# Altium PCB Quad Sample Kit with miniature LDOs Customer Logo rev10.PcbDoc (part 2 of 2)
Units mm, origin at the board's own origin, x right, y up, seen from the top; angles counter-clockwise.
Board outline 152.4 x 101.6 mm, 2 copper layers (Top Layer, Bottom Layer); 23 components, 21 nets, 109 pads, 47 vias.
Unrouted connection lines stored in the file: 13.

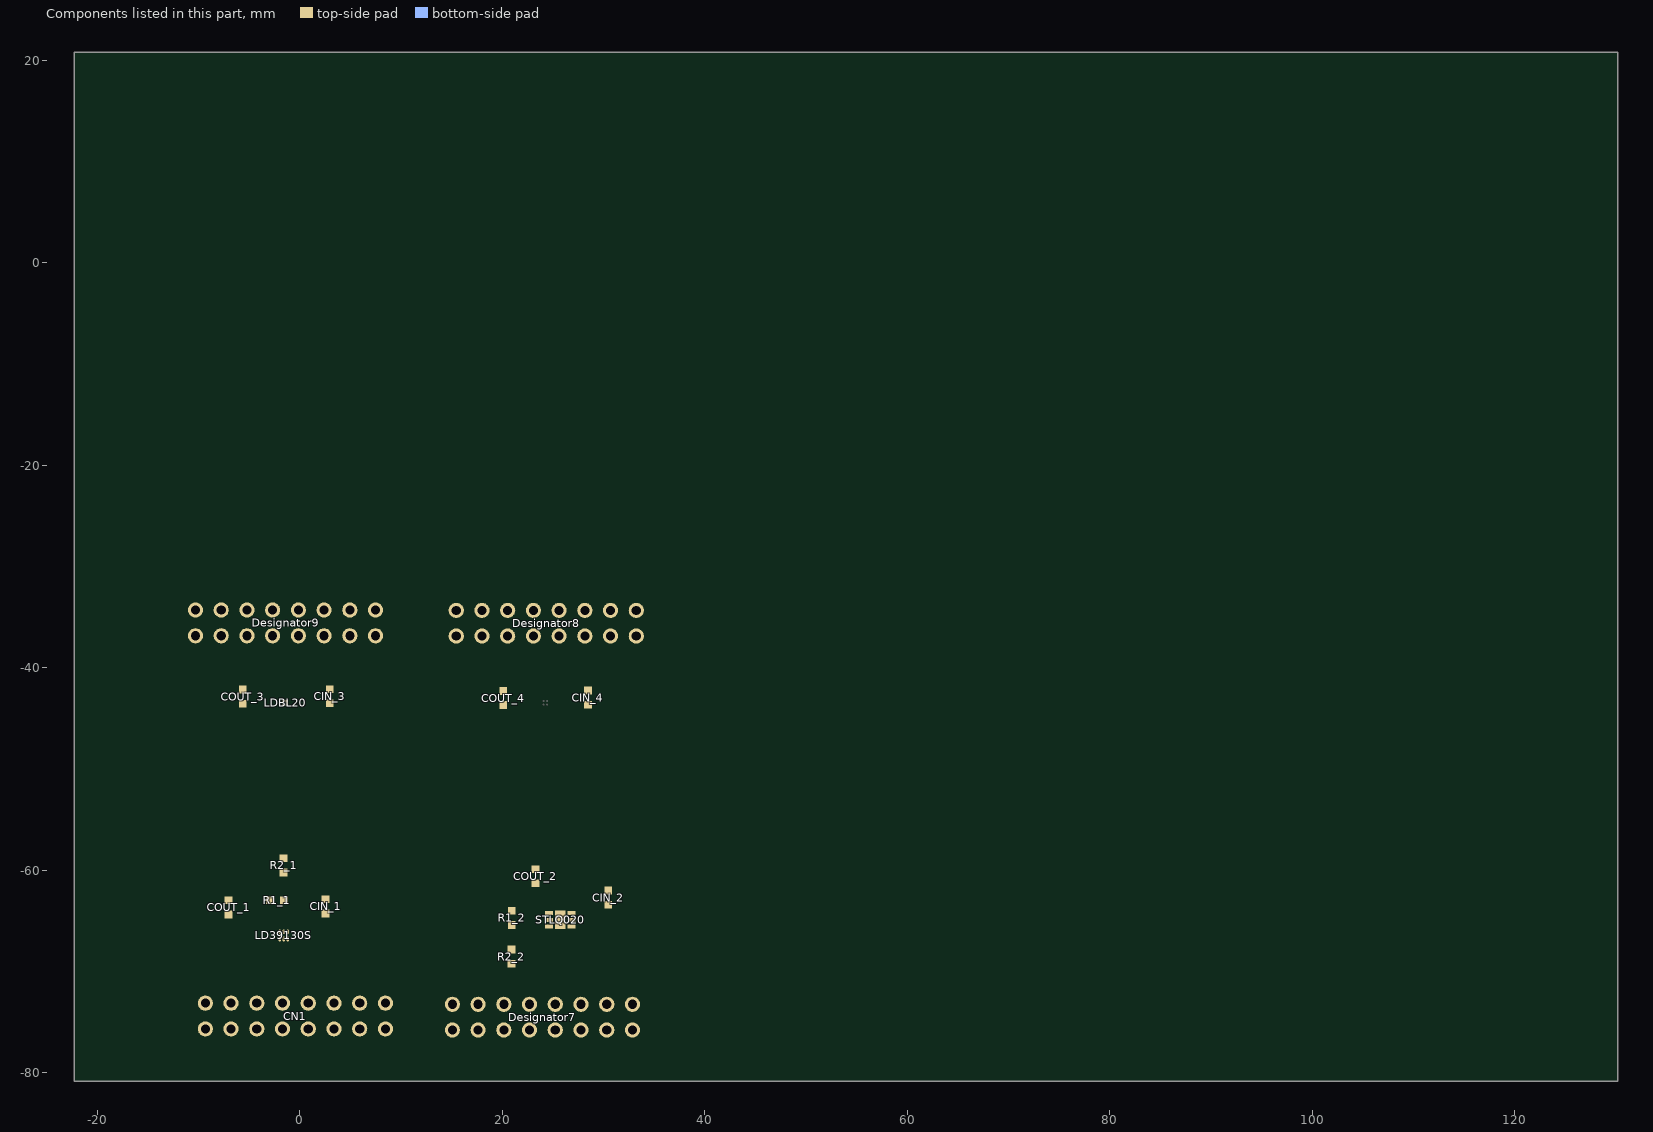
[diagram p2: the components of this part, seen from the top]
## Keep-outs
Bottom Overlay:
  lines w0.038: 1.384,-57.277 7.988,-57.277 ; 1.384,-57.252 7.988,-57.252 ; 1.384,-57.226 7.988,-57.226 ; 1.384,-57.201 7.988,-57.201 ; 1.384,-57.176 7.988,-57.176 ; 1.384,-57.15 7.988,-57.15 ; 1.384,-57.125 7.988,-57.125 ; 1.384,-57.099 7.988,-57.099 ; 1.384,-57.074 7.988,-57.074 ; 1.384,-57.049 7.988,-57.049 ; 1.384,-57.023 7.988,-57.023 ; 1.384,-56.998 1.587,-56.998 ; 1.384,-56.972 1.587,-56.972 ; 1.384,-56.947 1.587,-56.947 ; 1.384,-56.922 1.587,-56.922 ; 1.384,-56.896 1.587,-56.896 ; 1.384,-56.871 1.587,-56.871 ; 1.384,-56.845 1.587,-56.845 ; 1.384,-56.82 1.587,-56.82 ; 1.384,-56.795 1.587,-56.795 ; 1.384,-56.769 1.587,-56.769 ; 1.384,-56.744 1.587,-56.744 ; 1.384,-56.718 1.587,-56.718 ; 1.384,-56.693 1.587,-56.693 ; 1.384,-56.668 1.587,-56.668 ; 1.384,-56.642 1.587,-56.642 ; 1.384,-56.617 1.587,-56.617 ; 1.384,-56.591 1.587,-56.591 ; 1.384,-56.566 1.587,-56.566 ; 1.384,-56.541 1.587,-56.541 ; 1.384,-56.515 1.587,-56.515 ; 1.384,-56.49 1.587,-56.49 ; 1.384,-56.464 1.587,-56.464 ; 1.384,-56.439 1.587,-56.439 ; 1.384,-56.414 1.587,-56.414 ; 1.384,-56.388 1.587,-56.388 ; 1.384,-56.363 1.587,-56.363 ; 1.384,-56.337 1.587,-56.337 ; 1.384,-56.312 1.587,-56.312 ; 1.384,-56.287 1.587,-56.287 ; 1.384,-56.261 1.587,-56.261 ; 1.384,-56.236 1.587,-56.236 ; 1.384,-56.21 1.587,-56.21 ; 1.384,-56.185 1.587,-56.185 ; 1.384,-56.16 1.587,-56.16 ; 1.384,-56.134 1.587,-56.134 ; 1.384,-56.109 1.587,-56.109 ; 1.384,-56.083 1.587,-56.083 ; 1.384,-56.058 1.587,-56.058 ; 1.384,-56.033 1.587,-56.033 ; 1.384,-56.007 1.587,-56.007 ; 1.384,-55.982 1.587,-55.982 ; 1.384,-55.956 1.587,-55.956 ; 1.384,-55.931 1.587,-55.931 ; 1.384,-55.906 1.587,-55.906 ; 1.384,-55.88 1.587,-55.88 ; 1.384,-55.855 1.587,-55.855 ; 1.384,-55.829 1.587,-55.829 ; 1.384,-55.804 1.587,-55.804 ; 1.384,-55.779 1.587,-55.779 ; 1.384,-55.753 1.587,-55.753 ; 1.384,-55.728 1.587,-55.728 ; 1.384,-55.702 1.587,-55.702 ; 1.384,-55.677 1.587,-55.677 ; 1.384,-55.652 1.587,-55.652 ; 1.384,-55.626 1.587,-55.626 ; 1.384,-55.601 1.587,-55.601 ; 1.384,-55.575 1.587,-55.575 ; 1.384,-55.55 1.587,-55.55 ; 1.384,-55.525 1.587,-55.525 ; 1.384,-55.499 1.587,-55.499 ; 1.384,-55.474 1.587,-55.474 ; 1.384,-55.448 1.587,-55.448 ; 1.384,-55.423 1.587,-55.423 ; 1.384,-55.398 1.587,-55.398 ; 1.384,-55.372 1.587,-55.372 ; 1.384,-55.347 1.587,-55.347 ; 1.384,-55.321 1.587,-55.321 ; 1.384,-55.296 1.587,-55.296 ; 1.384,-55.271 1.587,-55.271 ; 1.384,-55.245 1.587,-55.245 ; 1.384,-55.22 1.587,-55.22 ; 1.384,-55.194 1.587,-55.194 ; 1.384,-55.169 1.587,-55.169 ; 1.384,-55.144 1.587,-55.144 ; 1.384,-55.118 1.587,-55.118 ; 1.384,-55.093 1.587,-55.093 ; 1.384,-55.067 1.587,-55.067 ; 1.384,-55.042 1.587,-55.042 ; 1.384,-55.017 1.587,-55.017 ; 1.384,-54.991 1.587,-54.991 ; 1.384,-54.966 1.587,-54.966 ; 1.384,-54.94 1.587,-54.94 ; 1.384,-54.915 1.587,-54.915 ; 1.384,-54.89 1.587,-54.89 ; 1.384,-54.864 1.587,-54.864 ; 1.384,-54.839 1.587,-54.839 ; 1.384,-54.813 1.587,-54.813 ; 1.384,-54.788 1.587,-54.788 ; 1.384,-54.763 1.587,-54.763 ; 1.384,-54.737 1.587,-54.737 ; 1.384,-54.712 1.587,-54.712 ; 1.384,-54.686 1.587,-54.686 ; 1.384,-54.661 1.587,-54.661 ; 1.384,-54.636 1.587,-54.636 ; 1.384,-54.61 1.587,-54.61 ; 1.384,-54.585 1.587,-54.585 ; 1.384,-54.559 1.587,-54.559 ; 1.384,-54.534 1.587,-54.534 ; 1.384,-54.509 1.587,-54.509 ; 1.384,-54.483 1.587,-54.483 ; 1.384,-54.458 1.587,-54.458 ; 1.384,-54.432 1.587,-54.432 ; 1.384,-54.407 1.587,-54.407 ; 1.384,-54.382 1.587,-54.382 ; 1.384,-54.356 1.587,-54.356 ; 1.384,-54.331 1.587,-54.331 ; 1.384,-54.305 1.587,-54.305 ; 1.384,-54.28 1.587,-54.28 ; 1.384,-54.255 1.587,-54.255 ; 1.384,-54.229 1.587,-54.229 ; 1.384,-54.204 1.587,-54.204 ; 1.384,-54.178 1.587,-54.178 ; 1.384,-54.153 1.587,-54.153 ; 1.384,-54.128 1.587,-54.128 ; 1.384,-54.102 1.587,-54.102 ; 1.384,-54.077 1.587,-54.077 ; 1.384,-54.051 1.587,-54.051 ; 1.384,-54.026 1.587,-54.026 ; 1.384,-54.001 1.587,-54.001 ; 1.384,-53.975 1.587,-53.975 ; 1.384,-53.95 1.587,-53.95 ; 1.384,-53.924 1.587,-53.924 ; 1.384,-53.899 1.587,-53.899 ; 1.384,-53.874 1.587,-53.874 ; 1.384,-53.848 1.587,-53.848 ; 1.384,-53.823 1.587,-53.823 ; 1.384,-53.797 1.587,-53.797 ; 1.384,-53.772 1.587,-53.772 ; 1.384,-53.747 1.587,-53.747 ; 1.384,-53.721 1.587,-53.721 ; 1.384,-53.696 1.587,-53.696 ; 1.384,-53.67 1.587,-53.67 ; 1.384,-53.645 1.587,-53.645 ; 1.384,-53.62 1.587,-53.62 ; 1.384,-53.594 1.587,-53.594 ; 1.384,-53.569 1.587,-53.569 ; 1.384,-53.543 1.587,-53.543 ; 1.384,-53.518 1.587,-53.518 ; 1.384,-53.493 1.587,-53.493 ; 1.384,-53.467 1.587,-53.467 ; 1.384,-53.442 1.587,-53.442 ; 1.384,-53.416 1.587,-53.416 ; 1.384,-53.391 1.587,-53.391 ; 1.384,-53.366 1.587,-53.366 ; 1.384,-53.34 1.587,-53.34 ; 1.384,-53.315 1.587,-53.315 ; 1.384,-53.289 1.587,-53.289 ; 1.384,-53.264 1.587,-53.264 ; 1.384,-53.239 1.587,-53.239 ; 1.384,-53.213 1.587,-53.213 ; 1.384,-53.188 1.587,-53.188 ; 1.384,-53.162 1.587,-53.162 ; 1.384,-53.137 1.587,-53.137 ; 1.384,-53.112 1.587,-53.112 ; 1.384,-53.086 1.587,-53.086 ; 1.384,-53.061 1.587,-53.061 ; 1.384,-53.035 1.587,-53.035 ; 1.384,-53.01 1.587,-53.01 ; 1.384,-52.985 1.587,-52.985 ; 1.384,-52.959 1.587,-52.959 ; 1.384,-52.934 1.587,-52.934 ; 1.384,-52.908 1.587,-52.908 ; 1.384,-52.883 1.587,-52.883 ; 1.384,-52.858 1.587,-52.858 ; 1.384,-52.832 1.587,-52.832 ; 1.384,-52.807 1.587,-52.807 ; 1.384,-52.781 1.587,-52.781 ; 1.384,-52.756 1.587,-52.756 ; 1.384,-52.731 1.587,-52.731 ; 1.384,-52.705 1.587,-52.705 ; 1.384,-52.68 1.587,-52.68 ; 1.384,-52.654 7.988,-52.654 ; 1.384,-52.629 7.988,-52.629 ; 1.384,-52.604 7.988,-52.604 ; 1.384,-52.578 7.988,-52.578 ; 1.384,-52.553 7.988,-52.553 ; 1.384,-52.527 7.988,-52.527 ; 1.384,-52.502 7.988,-52.502 ; 1.384,-52.477 7.988,-52.477 ; 1.849,-55.164 2.408,-55.164 ; 1.849,-55.139 2.408,-55.139 ; 1.849,-55.113 2.408,-55.113 ; 1.849,-55.088 2.408,-55.088 ; 1.849,-55.062 2.408,-55.062 ; 2.027,-55.621 2.23,-55.621 ; 2.027,-55.595 2.23,-55.595 ; 2.027,-55.57 2.23,-55.57 ; 2.027,-55.544 2.23,-55.544 ; 2.027,-55.519 2.23,-55.519 ; 2.027,-55.494 2.23,-55.494 ; 2.027,-55.468 2.23,-55.468 ; 2.027,-55.443 2.23,-55.443 ; 2.027,-55.417 2.23,-55.417 ; 2.027,-55.393 2.23,-55.393 ; 2.027,-55.367 2.23,-55.367 ; 2.027,-55.342 2.23,-55.342 ; 2.027,-55.316 2.23,-55.316 ; 2.027,-55.291 2.23,-55.291 ; 2.027,-55.266 2.23,-55.266 ; 2.027,-55.24 2.23,-55.24 ; 2.027,-55.215 2.23,-55.215 ; 2.027,-55.189 2.23,-55.189 ; 2.248,-54.128 2.679,-54.128 ; 2.248,-54.102 2.679,-54.102 ; 2.248,-54.077 2.654,-54.077 ; 2.248,-54.051 2.654,-54.051 ; 2.248,-54.026 2.654,-54.026 ; 2.248,-54.001 2.679,-54.001 ; 2.248,-53.975 2.73,-53.975 ; 2.248,-53.95 2.781,-53.95 ; 2.273,-54.178 3.34,-54.178 ; 2.273,-54.153 2.73,-54.153 ; 2.273,-53.924 2.908,-53.924 ; 2.273,-53.899 2.984,-53.899 ; 2.273,-53.874 3.06,-53.874 ; 2.273,-53.569 2.679,-53.569 ; 2.273,-53.543 2.705,-53.543 ; 2.273,-53.518 2.705,-53.518 ; 2.298,-54.229 3.314,-54.229 ; 2.298,-54.204 3.314,-54.204 ; 2.298,-53.848 3.111,-53.848 ; 2.298,-53.493 2.73,-53.493 ; 2.298,-53.467 2.756,-53.467 ; 2.298,-53.442 3.289,-53.442 ; 2.324,-54.255 3.289,-54.255 ; 2.324,-53.823 3.162,-53.823 ; 2.324,-53.797 3.213,-53.797 ; 2.324,-53.416 3.264,-53.416 ; 2.324,-53.391 3.264,-53.391 ; 2.349,-54.305 3.238,-54.305 ; 2.349,-54.28 3.264,-54.28 ; 2.349,-53.772 3.238,-53.772 ; 2.349,-53.594 2.679,-53.594 ; 2.349,-53.366 3.238,-53.366 ; 2.375,-53.34 3.213,-53.34 ; 2.4,-54.331 3.238,-54.331 ; 2.4,-53.747 3.264,-53.747 ; 2.4,-53.315 3.187,-53.315 ; 2.425,-54.356 3.187,-54.356 ; 2.425,-53.721 3.264,-53.721 ; 2.451,-56.388 2.629,-56.388 ; 2.451,-53.289 3.137,-53.289 ; 2.476,-56.439 2.908,-56.439 ; 2.476,-56.414 2.654,-56.414 ; 2.476,-56.16 2.629,-56.16 ; 2.476,-56.134 2.654,-56.134 ; 2.476,-56.109 2.908,-56.109 ; 2.476,-54.382 3.162,-54.382 ; 2.476,-53.696 3.289,-53.696 ; 2.484,-55.621 2.662,-55.621 ; 2.484,-55.595 2.687,-55.595 ; 2.484,-55.57 2.713,-55.57 ; 2.484,-55.544 2.713,-55.544 ; 2.484,-55.519 2.738,-55.519 ; 2.484,-55.494 2.764,-55.494 ; 2.484,-55.468 2.764,-55.468 ; 2.484,-55.443 2.789,-55.443 ; 2.484,-55.417 2.814,-55.417 ; 2.484,-55.393 2.84,-55.393 ; 2.484,-55.367 2.84,-55.367 ; 2.484,-55.342 2.662,-55.342 ; 2.484,-55.316 2.662,-55.316 ; 2.484,-55.291 2.662,-55.291 ; 2.484,-55.266 2.662,-55.266 ; 2.484,-55.24 2.662,-55.24 ; 2.484,-55.215 2.662,-55.215 ; 2.484,-55.189 2.662,-55.189 ; 2.484,-55.164 2.662,-55.164 ; 2.484,-55.139 2.662,-55.139 ; 2.484,-55.113 2.662,-55.113 ; 2.484,-55.088 2.662,-55.088 ; 2.484,-55.062 2.662,-55.062 ; 2.502,-56.464 2.883,-56.464 ; 2.502,-56.363 2.629,-56.363 ; 2.502,-56.083 2.908,-56.083 ; 2.502,-53.264 3.086,-53.264 ; 2.527,-56.49 2.883,-56.49 ; 2.527,-56.058 2.883,-56.058 ; 2.527,-54.407 3.086,-54.407 ; 2.552,-56.515 2.832,-56.515 ; 2.552,-56.033 2.832,-56.033 ; 2.552,-53.67 3.289,-53.67 ; 2.603,-56.337 2.629,-56.337 ; 2.603,-56.185 2.629,-56.185 ; 2.603,-54.432 3.01,-54.432 ; 2.603,-53.239 2.984,-53.239 ; 2.629,-56.541 2.756,-56.541 ; 2.629,-56.007 2.756,-56.007 ; 2.629,-53.645 3.314,-53.645 ; 2.687,-55.342 2.865,-55.342 ; 2.713,-55.316 3.068,-55.316 ; 2.713,-55.291 3.068,-55.291 ; 2.73,-53.62 3.314,-53.62 ; 2.738,-55.266 3.068,-55.266 ; 2.756,-56.414 2.933,-56.414 ; 2.756,-56.16 2.933,-56.16 ; 2.756,-56.134 2.933,-56.134 ; 2.764,-55.24 3.068,-55.24 ; 2.781,-56.388 2.933,-56.388 ; 2.781,-56.363 2.933,-56.363 ; 2.781,-56.337 2.933,-56.337 ; 2.781,-56.312 2.959,-56.312 ; 2.781,-56.287 2.959,-56.287 ; 2.781,-56.261 2.959,-56.261 ; 2.781,-56.236 2.959,-56.236 ; 2.781,-56.21 2.959,-56.21 ; 2.781,-56.185 2.933,-56.185 ; 2.789,-55.215 3.068,-55.215 ; 2.789,-55.189 3.068,-55.189 ; 2.814,-55.164 3.068,-55.164 ; 2.832,-54.153 3.34,-54.153 ; 2.832,-53.594 3.314,-53.594 ; 2.84,-55.139 3.068,-55.139 ; 2.84,-55.113 3.068,-55.113 ; 2.857,-53.467 3.289,-53.467 ; 2.865,-55.088 3.068,-55.088 ; 2.883,-54.128 3.34,-54.128 ; 2.883,-53.569 3.314,-53.569 ; 2.883,-53.493 3.314,-53.493 ; 2.891,-55.621 3.068,-55.621 ; 2.891,-55.595 3.068,-55.595 ; 2.891,-55.57 3.068,-55.57 ; 2.891,-55.544 3.068,-55.544 ; 2.891,-55.519 3.068,-55.519 ; 2.891,-55.494 3.068,-55.494 ; 2.891,-55.468 3.068,-55.468 ; 2.891,-55.443 3.068,-55.443 ; 2.891,-55.417 3.068,-55.417 ; 2.891,-55.393 3.068,-55.393 ; 2.891,-55.367 3.068,-55.367 ; 2.891,-55.342 3.068,-55.342 ; 2.891,-55.062 3.068,-55.062 ; 2.908,-54.102 3.365,-54.102 ; 2.908,-53.543 3.314,-53.543 ; 2.908,-53.518 3.314,-53.518 ; 2.933,-54.077 3.365,-54.077 ; 2.933,-54.051 3.365,-54.051 ; 2.959,-54.026 3.365,-54.026 ; 2.959,-54.001 3.314,-54.001 ; 3.035,-56.541 3.492,-56.541 ; 3.035,-56.515 3.492,-56.515 ; 3.035,-56.49 3.492,-56.49 ; 3.035,-56.464 3.492,-56.464 ; 3.035,-56.439 3.492,-56.439 ; 3.035,-56.109 3.492,-56.109 ; 3.035,-56.083 3.492,-56.083 ; 3.035,-56.058 3.492,-56.058 ; 3.035,-56.033 3.492,-56.033 ; 3.035,-56.007 3.492,-56.007 ; 3.06,-56.312 3.492,-56.312 ; 3.06,-56.287 3.492,-56.287 ; 3.06,-56.261 3.492,-56.261 ; 3.06,-56.236 3.492,-56.236 ; 3.06,-56.21 3.492,-56.21 ; 3.144,-55.611 3.347,-55.611 ; 3.169,-55.585 3.372,-55.585 ; 3.169,-55.56 3.372,-55.56 ; 3.169,-55.534 3.372,-55.534 ; 3.195,-55.509 3.753,-55.509 ; 3.195,-55.484 3.753,-55.484 ; 3.195,-55.458 3.753,-55.458 ; 3.22,-55.433 3.728,-55.433 ; 3.22,-55.407 3.728,-55.407 ; 3.22,-55.382 3.728,-55.382 ; 3.245,-55.357 3.423,-55.357 ; 3.245,-55.332 3.423,-55.332 ; 3.245,-55.306 3.449,-55.306 ; 3.271,-55.281 3.449,-55.281 ; 3.271,-55.255 3.449,-55.255 ; 3.271,-55.23 3.677,-55.23 ; 3.296,-55.205 3.652,-55.205 ; 3.296,-55.179 3.652,-55.179 ; 3.296,-55.154 3.652,-55.154 ; 3.314,-56.414 3.492,-56.414 ; 3.314,-56.388 3.492,-56.388 ; 3.314,-56.363 3.492,-56.363 ; 3.314,-56.337 3.492,-56.337 ; 3.314,-56.185 3.492,-56.185 ; 3.314,-56.16 3.492,-56.16 ; 3.314,-56.134 3.492,-56.134 ; 3.322,-55.128 3.626,-55.128 ; 3.322,-55.103 3.626,-55.103 ; 3.322,-55.078 3.626,-55.078 ; 3.347,-55.052 3.601,-55.052 ; 3.499,-55.306 3.703,-55.306 ; 3.499,-55.281 3.677,-55.281 ; 3.499,-55.255 3.677,-55.255 ; 3.518,-54.407 3.924,-54.407 ; 3.518,-54.382 3.924,-54.382 ; 3.518,-54.356 3.924,-54.356 ; 3.518,-54.331 3.924,-54.331 ; 3.518,-54.305 3.924,-54.305 ; 3.518,-54.28 3.924,-54.28 ; 3.518,-54.255 3.924,-54.255 ; 3.518,-54.229 3.924,-54.229 ; 3.518,-54.204 3.924,-54.204 ; 3.518,-54.178 3.924,-54.178 ; 3.518,-54.153 3.924,-54.153 ; 3.518,-54.128 3.924,-54.128 ; 3.518,-54.102 3.924,-54.102 ; 3.518,-54.077 3.924,-54.077 ; 3.518,-54.051 3.924,-54.051 ; 3.518,-54.026 3.924,-54.026 ; 3.518,-54.001 3.924,-54.001 ; 3.518,-53.975 3.924,-53.975 ; 3.518,-53.95 4.635,-53.95 ; 3.518,-53.924 4.635,-53.924 ; 3.518,-53.899 4.635,-53.899 ; 3.518,-53.874 4.635,-53.874 ; 3.518,-53.848 4.635,-53.848 ; 3.518,-53.823 4.635,-53.823 ; 3.518,-53.797 4.635,-53.797 ; 3.518,-53.772 4.635,-53.772 ; 3.518,-53.747 4.635,-53.747 ; 3.518,-53.721 4.635,-53.721 ; 3.518,-53.696 4.635,-53.696 ; 3.518,-53.67 4.635,-53.67 ; 3.518,-53.645 3.924,-53.645 ; 3.518,-53.62 3.924,-53.62 ; 3.518,-53.594 3.924,-53.594 ; 3.518,-53.569 3.924,-53.569 ; 3.518,-53.543 3.924,-53.543 ; 3.518,-53.518 3.924,-53.518 ; 3.518,-53.493 3.924,-53.493 ; 3.518,-53.467 3.924,-53.467 ; 3.518,-53.442 3.924,-53.442 ; 3.518,-53.416 3.924,-53.416 ; 3.518,-53.391 3.924,-53.391 ; 3.518,-53.366 3.924,-53.366 ; 3.518,-53.34 3.924,-53.34 ; 3.518,-53.315 3.924,-53.315 ; 3.518,-53.289 3.924,-53.289 ; 3.518,-53.264 3.924,-53.264 ; 3.525,-55.357 3.703,-55.357 ; 3.525,-55.332 3.703,-55.332 ; 3.543,-56.007 3.619,-56.007 ; 3.568,-56.109 3.645,-56.109 ; 3.568,-56.083 3.645,-56.083 ; 3.568,-56.058 3.619,-56.058 ; 3.568,-56.033 3.619,-56.033 ; 3.576,-55.585 3.779,-55.585 ; 3.576,-55.56 3.779,-55.56 ; 3.576,-55.534 3.779,-55.534 ; 3.594,-56.236 3.67,-56.236 ; 3.594,-56.21 3.67,-56.21 ; 3.594,-56.185 3.645,-56.185 ; 3.594,-56.16 3.645,-56.16 ; 3.594,-56.134 3.645,-56.134 ; 3.601,-55.611 3.804,-55.611 ; 3.619,-56.337 3.695,-56.337 ; 3.619,-56.312 3.695,-56.312 ; 3.619,-56.287 3.67,-56.287 ; 3.619,-56.261 3.67,-56.261 ; 3.645,-56.464 3.721,-56.464 ; 3.645,-56.439 3.721,-56.439 ; 3.645,-56.414 3.695,-56.414 ; 3.645,-56.388 3.695,-56.388 ; 3.645,-56.363 3.695,-56.363 ; 3.67,-56.541 3.746,-56.541 ; 3.67,-56.515 3.721,-56.515 ; 3.67,-56.49 3.721,-56.49 ; 3.797,-56.388 3.949,-56.388 ; 3.797,-56.363 3.949,-56.363 ; 3.797,-56.337 3.949,-56.337 ; 3.797,-56.312 3.949,-56.312 ; 3.822,-56.439 3.975,-56.439 ; 3.822,-56.414 3.949,-56.414 ; 3.822,-56.287 3.975,-56.287 ; 3.822,-56.261 4.178,-56.261 ; 3.822,-56.109 4.153,-56.109 ; 3.822,-56.083 4.153,-56.083 ; 3.822,-56.058 4.153,-56.058 ; 3.822,-56.033 4.153,-56.033 ; 3.822,-56.007 4.153,-56.007 ; 3.848,-56.49 4.178,-56.49 ; 3.848,-56.464 4.203,-56.464 ; 3.848,-56.236 4.178,-56.236 ; 3.873,-56.515 4.153,-56.515 ; 3.873,-56.21 4.178,-56.21 ; 3.915,-55.611 4.118,-55.611 ; 3.915,-55.585 4.118,-55.585 ; 3.915,-55.56 4.118,-55.56 ; 3.915,-55.534 4.118,-55.534 ; 3.915,-55.509 4.118,-55.509 ; 3.915,-55.484 4.118,-55.484 ; 3.915,-55.458 4.118,-55.458 ; 3.915,-55.433 4.118,-55.433 ; 3.915,-55.407 4.118,-55.407 ; 3.915,-55.382 4.118,-55.382 ; 3.915,-55.357 4.118,-55.357 ; 3.915,-55.332 4.118,-55.332 ; 3.915,-55.306 4.118,-55.306 ; 3.915,-55.281 4.118,-55.281 ; 3.915,-55.255 4.118,-55.255 ; 3.915,-55.23 4.118,-55.23 ; 3.915,-55.205 4.118,-55.205 ; 3.915,-55.179 4.118,-55.179 ; 3.915,-55.154 4.118,-55.154 ; 3.915,-55.128 4.118,-55.128 ; 3.915,-55.103 4.118,-55.103 ; 3.915,-55.078 4.118,-55.078 ; 3.915,-55.052 4.118,-55.052 ; 3.924,-56.185 4,-56.185 ; 3.949,-56.541 4.076,-56.541 ; 4.051,-56.439 4.203,-56.439 ; 4.051,-56.287 4.178,-56.287 ; 4.051,-56.185 4.178,-56.185 ; 4.051,-56.16 4.178,-56.16 ; 4.051,-56.134 4.178,-56.134 ; 4.076,-56.414 4.203,-56.414 ; 4.076,-56.388 4.102,-56.388 ; 4.22,-55.585 4.677,-55.585 ; 4.22,-55.56 4.677,-55.56 ; 4.22,-55.534 4.677,-55.534 ; 4.22,-55.509 4.677,-55.509 ; 4.22,-55.484 4.677,-55.484 ; 4.229,-54.407 4.635,-54.407 ; 4.229,-54.382 4.635,-54.382 ; 4.229,-54.356 4.635,-54.356 ; 4.229,-54.331 4.635,-54.331 ; 4.229,-54.305 4.635,-54.305 ; 4.229,-54.28 4.635,-54.28 ; 4.229,-54.255 4.635,-54.255 ; 4.229,-54.229 4.635,-54.229 ; 4.229,-54.204 4.635,-54.204 ; 4.229,-54.178 4.635,-54.178 ; 4.229,-54.153 4.635,-54.153 ; 4.229,-54.128 4.635,-54.128 ; 4.229,-54.102 4.635,-54.102 ; 4.229,-54.077 4.635,-54.077 ; 4.229,-54.051 4.635,-54.051 ; 4.229,-54.026 4.635,-54.026 ; 4.229,-54.001 4.635,-54.001 ; 4.229,-53.975 4.635,-53.975 ; 4.229,-53.645 4.635,-53.645 ; 4.229,-53.62 4.635,-53.62 ; 4.229,-53.594 4.635,-53.594 ; 4.229,-53.569 4.635,-53.569 ; 4.229,-53.543 4.635,-53.543 ; 4.229,-53.518 4.635,-53.518 ; 4.229,-53.493 4.635,-53.493 ; 4.229,-53.467 4.635,-53.467 ; 4.229,-53.442 4.635,-53.442 ; 4.229,-53.416 4.635,-53.416 ; 4.229,-53.391 4.635,-53.391 ; 4.229,-53.366 4.635,-53.366 ; 4.229,-53.34 4.635,-53.34 ; 4.229,-53.315 4.635,-53.315 ; 4.229,-53.289 4.635,-53.289 ; 4.229,-53.264 4.635,-53.264 ; 4.305,-56.337 4.457,-56.337 ; 4.305,-56.312 4.457,-56.312 ; 4.305,-56.287 4.686,-56.287 ; 4.305,-56.261 4.711,-56.261 ; 4.305,-56.236 4.483,-56.236 ; 4.305,-56.21 4.457,-56.21 ; 4.33,-56.414 4.483,-56.414 ; 4.33,-56.388 4.457,-56.388 ; 4.33,-56.363 4.457,-56.363 ; 4.33,-56.185 4.457,-56.185 ; 4.33,-56.16 4.457,-56.16 ; 4.33,-56.134 4.457,-56.134 ; 4.33,-56.109 4.483,-56.109 ; 4.356,-56.464 4.711,-56.464 ; 4.356,-56.439 4.483,-56.439 ; 4.356,-56.083 4.711,-56.083 ; 4.381,-56.49 4.686,-56.49 ; 4.381,-56.058 4.686,-56.058 ; 4.407,-56.515 4.661,-56.515 ; 4.407,-56.033 4.661,-56.033 ; 4.474,-55.458 4.677,-55.458 ; 4.474,-55.433 4.677,-55.433 ; 4.474,-55.407 4.677,-55.407 ; 4.474,-55.382 4.677,-55.382 ; 4.474,-55.357 4.677,-55.357 ; 4.474,-55.332 4.677,-55.332 ; 4.474,-55.306 4.677,-55.306 ; 4.474,-55.281 4.677,-55.281 ; 4.474,-55.255 4.677,-55.255 ; 4.474,-55.23 4.677,-55.23 ; 4.474,-55.205 4.677,-55.205 ; 4.474,-55.179 4.677,-55.179 ; 4.474,-55.154 4.677,-55.154 ; 4.474,-55.128 4.677,-55.128 ; 4.474,-55.103 4.677,-55.103 ; 4.474,-55.078 4.677,-55.078 ; 4.474,-55.052 4.677,-55.052 ; 4.483,-56.541 4.61,-56.541 ; 4.483,-56.312 4.661,-56.312 ; 4.483,-56.007 4.584,-56.007 ; 4.534,-56.337 4.61,-56.337 ; 4.559,-56.236 4.711,-56.236 ; 4.559,-56.109 4.711,-56.109 ; 4.584,-56.439 4.711,-56.439 ; 4.584,-56.414 4.635,-56.414 ; 4.584,-56.21 4.737,-56.21 ; 4.584,-56.185 4.737,-56.185 ; 4.584,-56.16 4.737,-56.16 ; 4.584,-56.134 4.737,-56.134 ; 4.753,-55.255 4.956,-55.255 ; 4.753,-55.23 4.956,-55.23 ; 4.753,-55.205 4.956,-55.205 ; 4.753,-55.179 4.981,-55.179 ; 4.762,-56.007 4.838,-56.007 ; 4.779,-55.332 5.261,-55.332 ; 4.779,-55.306 5.261,-55.306 ; 4.779,-55.281 4.981,-55.281 ; 4.779,-55.154 5.261,-55.154 ; 4.779,-55.128 5.261,-55.128 ; 4.788,-56.109 4.864,-56.109 ; 4.788,-56.083 4.864,-56.083 ; 4.788,-56.058 4.838,-56.058 ; 4.788,-56.033 4.838,-56.033 ; 4.788,-54.102 5.194,-54.102 ; 4.788,-54.077 5.169,-54.077 ; 4.788,-54.051 5.169,-54.051 ; 4.788,-54.026 5.169,-54.026 ; 4.788,-54.001 5.169,-54.001 ; 4.788,-53.975 5.169,-53.975 ; 4.788,-53.95 5.169,-53.95 ; 4.788,-53.924 5.169,-53.924 ; 4.788,-53.899 5.169,-53.899 ; 4.788,-53.874 5.194,-53.874 ; 4.804,-55.357 5.261,-55.357 ; 4.804,-55.103 5.261,-55.103 ; 4.813,-56.236 4.889,-56.236 ; 4.813,-56.21 4.889,-56.21 ; 4.813,-56.185 4.864,-56.185 ; 4.813,-56.16 4.864,-56.16 ; 4.813,-56.134 4.864,-56.134 ; 4.813,-54.178 5.219,-54.178 ; 4.813,-54.153 5.194,-54.153 ; 4.813,-54.128 5.194,-54.128 ; 4.813,-53.848 5.194,-53.848 ; 4.813,-53.823 5.194,-53.823 ; 4.813,-53.797 5.219,-53.797 ; 4.829,-55.382 5.261,-55.382 ; 4.829,-55.078 5.261,-55.078 ; 4.838,-56.337 4.915,-56.337 ; 4.838,-56.312 4.915,-56.312 ; 4.838,-56.287 4.889,-56.287 ; 4.838,-56.261 4.889,-56.261 ; 4.838,-54.229 5.753,-54.229 ; 4.838,-54.204 5.27,-54.204 ; 4.838,-53.772 5.27,-53.772 ; 4.838,-53.747 5.753,-53.747 ; 4.854,-55.052 5.261,-55.052 ; 4.864,-56.464 4.94,-56.464 ; 4.864,-56.439 4.94,-56.439 ; 4.864,-56.414 4.915,-56.414 ; 4.864,-56.388 4.915,-56.388 ; 4.864,-56.363 4.915,-56.363 ; 4.864,-54.255 5.727,-54.255 ; 4.864,-53.721 5.727,-53.721 ; 4.88,-55.407 5.261,-55.407 ; 4.889,-56.541 4.965,-56.541 ; 4.889,-56.515 4.94,-56.515 ; 4.889,-56.49 4.94,-56.49 ; 4.889,-54.28 5.702,-54.28 ; 4.889,-53.696 5.702,-53.696 ; 4.915,-54.305 5.677,-54.305 ; 4.915,-53.67 5.677,-53.67 ; 4.94,-54.331 5.651,-54.331 ; 4.94,-53.645 5.651,-53.645 ; 4.965,-54.356 5.626,-54.356 ; 4.965,-53.62 5.626,-53.62 ; 4.991,-53.594 5.575,-53.594 ; 5.016,-56.541 5.448,-56.541 ; 5.016,-56.515 5.423,-56.515 ; 5.016,-56.49 5.423,-56.49 ; 5.016,-56.464 5.423,-56.464 ; 5.016,-56.439 5.397,-56.439 ; 5.016,-56.185 5.169,-56.185 ; 5.016,-56.16 5.169,-56.16 ; 5.016,-56.134 5.169,-56.134 ; 5.016,-54.382 5.575,-54.382 ; 5.042,-56.236 5.194,-56.236 ; 5.042,-56.21 5.169,-56.21 ; 5.042,-56.109 5.194,-56.109 ; 5.042,-56.083 5.423,-56.083 ; 5.058,-55.611 5.261,-55.611 ; 5.058,-55.585 5.261,-55.585 ; 5.058,-55.56 5.261,-55.56 ; 5.058,-55.534 5.261,-55.534 ; 5.058,-55.509 5.261,-55.509 ; 5.058,-55.484 5.261,-55.484 ; 5.058,-55.458 5.261,-55.458 ; 5.058,-55.433 5.261,-55.433 ; 5.058,-55.281 5.261,-55.281 ; 5.058,-55.255 5.261,-55.255 ; 5.058,-55.23 5.261,-55.23 ; 5.058,-55.205 5.261,-55.205 ; 5.058,-55.179 5.261,-55.179 ; 5.067,-56.261 5.219,-56.261 ; 5.067,-56.058 5.397,-56.058 ; 5.067,-54.407 5.524,-54.407 ; 5.067,-53.569 5.524,-53.569 ; 5.092,-56.287 5.245,-56.287 ; 5.092,-56.033 5.372,-56.033 ; 5.118,-56.312 5.296,-56.312 ; 5.143,-56.337 5.321,-56.337 ; 5.143,-54.432 5.448,-54.432 ; 5.143,-53.543 5.448,-53.543 ; 5.169,-56.363 5.346,-56.363 ; 5.169,-56.007 5.296,-56.007 ; 5.219,-56.388 5.372,-56.388 ; 5.245,-56.414 5.397,-56.414 ; 5.27,-56.109 5.423,-56.109 ; 5.296,-56.16 5.346,-56.16 ; 5.296,-56.134 5.448,-56.134 ; 5.321,-54.204 5.753,-54.204 ; 5.321,-53.772 5.753,-53.772 ; 5.372,-54.178 5.778,-54.178 ; 5.372,-53.797 5.778,-53.797 ; 5.397,-54.153 5.778,-54.153 ; 5.397,-54.128 5.778,-54.128 ; 5.397,-54.102 5.804,-54.102 ; 5.397,-53.874 5.804,-53.874 ; 5.397,-53.848 5.778,-53.848 ; 5.397,-53.823 5.778,-53.823 ; 5.423,-54.077 5.804,-54.077 ; 5.423,-54.051 5.804,-54.051 ; 5.423,-54.026 5.804,-54.026 ; 5.423,-54.001 5.804,-54.001 ; 5.423,-53.975 5.804,-53.975 ; 5.423,-53.95 5.804,-53.95 ; 5.423,-53.924 5.804,-53.924 ; 5.423,-53.899 5.804,-53.899 ; 5.524,-56.337 5.677,-56.337 ; 5.524,-56.312 5.677,-56.312 ; 5.524,-56.287 5.677,-56.287 ; 5.524,-56.261 5.677,-56.261 ; 5.524,-56.236 5.677,-56.236 ; 5.524,-56.21 5.677,-56.21 ; 5.55,-56.439 5.702,-56.439 ; 5.55,-56.414 5.677,-56.414 ; 5.55,-56.388 5.677,-56.388 ; 5.55,-56.363 5.677,-56.363 ; 5.55,-56.185 5.677,-56.185 ; 5.55,-56.16 5.677,-56.16 ; 5.55,-56.134 5.677,-56.134 ; 5.55,-56.109 5.702,-56.109 ; 5.575,-56.49 5.905,-56.49 ; 5.575,-56.464 5.905,-56.464 ; 5.575,-56.083 5.905,-56.083 ; 5.575,-56.058 5.905,-56.058 ; 5.6,-56.515 5.854,-56.515 ; 5.626,-56.033 5.854,-56.033 ; 5.677,-56.541 5.804,-56.541 ; 5.677,-56.007 5.804,-56.007 ; 5.778,-56.439 5.931,-56.439 ; 5.778,-56.109 5.931,-56.109 ; 5.804,-56.414 5.931,-56.414 ; 5.804,-56.388 5.931,-56.388 ; 5.804,-56.363 5.931,-56.363 ; 5.804,-56.337 5.956,-56.337 ; 5.804,-56.312 5.956,-56.312 ; 5.804,-56.287 5.956,-56.287 ; 5.804,-56.261 5.956,-56.261 ; 5.804,-56.236 5.956,-56.236 ; 5.804,-56.21 5.956,-56.21 ; 5.804,-56.185 5.931,-56.185 ; 5.804,-56.16 5.931,-56.16 ; 5.804,-56.134 5.931,-56.134 ; 5.804,-54.382 6.261,-54.382 ; 5.829,-54.407 6.261,-54.407 ; 5.829,-54.356 6.286,-54.356 ; 5.854,-54.331 6.312,-54.331 ; 5.854,-54.305 6.312,-54.305 ; 5.88,-54.28 6.337,-54.28 ; 5.88,-54.255 6.337,-54.255 ; 5.905,-54.229 6.362,-54.229 ; 5.905,-53.67 6.337,-53.67 ; 5.905,-53.645 6.312,-53.645 ; 5.905,-53.62 6.312,-53.62 ; 5.905,-53.594 6.312,-53.594 ; 5.905,-53.569 6.337,-53.569 ; 5.905,-53.543 6.388,-53.543 ; 5.905,-53.518 6.997,-53.518 ; 5.905,-53.493 6.997,-53.493 ; 5.931,-54.204 6.388,-54.204 ; 5.931,-54.178 6.388,-54.178 ; 5.931,-53.747 6.997,-53.747 ; 5.931,-53.721 6.997,-53.721 ; 5.931,-53.696 6.413,-53.696 ; 5.931,-53.467 6.997,-53.467 ; 5.931,-53.442 6.997,-53.442 ; 5.956,-54.153 6.413,-54.153 ; 5.956,-54.128 6.413,-54.128 ; 5.956,-53.772 6.997,-53.772 ; 5.956,-53.416 6.997,-53.416 ; 5.956,-53.391 6.997,-53.391 ; 5.981,-54.102 6.439,-54.102 ; 5.981,-54.077 6.439,-54.077 ; 5.981,-53.797 6.997,-53.797 ; 5.981,-53.366 6.997,-53.366 ; 6.007,-54.051 6.464,-54.051 ; 6.007,-53.823 6.997,-53.823 ; 6.007,-53.34 6.997,-53.34 ; 6.032,-56.337 6.185,-56.337 ; 6.032,-56.312 6.185,-56.312 ; 6.032,-56.287 6.185,-56.287 ; 6.032,-56.261 6.185,-56.261 ; 6.032,-56.236 6.185,-56.236 ; 6.032,-56.21 6.185,-56.21 ; 6.032,-54.026 6.489,-54.026 ; 6.032,-53.848 6.997,-53.848 ; 6.032,-53.315 6.997,-53.315 ; 6.058,-56.439 6.21,-56.439 ; 6.058,-56.414 6.185,-56.414 ; 6.058,-56.388 6.185,-56.388 ; 6.058,-56.363 6.185,-56.363 ; 6.058,-56.185 6.185,-56.185 ; 6.058,-56.16 6.185,-56.16 ; 6.058,-56.134 6.185,-56.134 ; 6.058,-56.109 6.21,-56.109 ; 6.058,-54.001 6.489,-54.001 ; 6.058,-53.975 6.54,-53.975 ; 6.058,-53.874 6.997,-53.874 ; 6.083,-56.49 6.413,-56.49 ; 6.083,-56.464 6.413,-56.464 ; 6.083,-56.083 6.413,-56.083 ; 6.083,-56.058 6.413,-56.058 ; 6.083,-53.95 6.997,-53.95 ; 6.083,-53.289 6.997,-53.289 ; 6.108,-56.515 6.362,-56.515 ; 6.108,-53.899 6.997,-53.899 ; 6.134,-56.033 6.362,-56.033 ; 6.134,-53.924 6.997,-53.924 ; 6.159,-53.264 6.997,-53.264 ; 6.185,-56.541 6.312,-56.541 ; 6.185,-56.007 6.312,-56.007 ; 6.197,-55.382 6.401,-55.382 ; 6.197,-55.357 6.401,-55.357 ; 6.197,-55.332 6.401,-55.332 ; 6.197,-55.306 6.401,-55.306 ; 6.197,-55.281 6.401,-55.281 ; 6.223,-55.458 6.426,-55.458 ; 6.223,-55.433 6.401,-55.433 ; 6.223,-55.407 6.401,-55.407 ; 6.223,-55.255 6.401,-55.255 ; 6.223,-55.23 6.401,-55.23 ; 6.223,-55.205 6.426,-55.205 ; 6.248,-55.509 6.782,-55.509 ; 6.248,-55.484 6.451,-55.484 ; 6.248,-55.179 6.477,-55.179 ; 6.248,-55.154 6.782,-55.154 ; 6.274,-55.534 6.756,-55.534 ; 6.274,-55.128 6.756,-55.128 ; 6.286,-56.439 6.439,-56.439 ; 6.286,-56.109 6.439,-56.109 ; 6.299,-55.56 6.731,-55.56 ; 6.299,-55.103 6.731,-55.103 ; 6.312,-56.414 6.439,-56.414 ; 6.312,-56.388 6.439,-56.388 ; 6.312,-56.363 6.439,-56.363 ; 6.312,-56.337 6.464,-56.337 ; 6.312,-56.312 6.464,-56.312 ; 6.312,-56.287 6.464,-56.287 ; 6.312,-56.261 6.464,-56.261 ; 6.312,-56.236 6.464,-56.236 ; 6.312,-56.21 6.464,-56.21 ; 6.312,-56.185 6.439,-56.185 ; 6.312,-56.16 6.439,-56.16 ; 6.312,-56.134 6.439,-56.134 ; 6.324,-55.585 6.68,-55.585 ; 6.35,-55.078 6.68,-55.078 ; 6.401,-55.611 6.629,-55.611 ; 6.401,-55.052 6.629,-55.052 ; 6.54,-56.541 6.972,-56.541 ; 6.54,-56.515 6.947,-56.515 ; 6.54,-56.49 6.947,-56.49 ; 6.54,-56.464 6.947,-56.464 ; 6.54,-56.439 6.921,-56.439 ; 6.54,-56.185 6.693,-56.185 ; 6.54,-56.16 6.693,-56.16 ; 6.54,-56.134 6.693,-56.134 ; 6.553,-55.484 6.782,-55.484 ; 6.553,-55.179 6.782,-55.179 ; 6.566,-56.236 6.718,-56.236 ; 6.566,-56.21 6.693,-56.21 ; 6.566,-56.109 6.718,-56.109 ; 6.566,-56.083 6.947,-56.083 ; 6.591,-56.261 6.743,-56.261 ; 6.591,-56.058 6.921,-56.058 ; 6.591,-54.407 6.997,-54.407 ; 6.591,-54.382 6.997,-54.382 ; 6.591,-54.356 6.997,-54.356 ; 6.591,-54.331 6.997,-54.331 ; 6.591,-54.305 6.997,-54.305 ; 6.591,-54.28 6.997,-54.28 ; 6.591,-54.255 6.997,-54.255 ; 6.591,-54.229 6.997,-54.229 ; 6.591,-54.204 6.997,-54.204 ; 6.591,-54.178 6.997,-54.178 ; 6.591,-54.153 6.997,-54.153 ; 6.591,-54.128 6.997,-54.128 ; 6.591,-54.102 6.997,-54.102 ; 6.591,-54.077 6.997,-54.077 ; 6.591,-54.051 6.997,-54.051 ; 6.591,-54.026 6.997,-54.026 ; 6.591,-54.001 6.997,-54.001 ; 6.591,-53.975 6.997,-53.975 ; 6.591,-53.696 6.997,-53.696 ; 6.591,-53.67 6.997,-53.67 ; 6.591,-53.645 6.997,-53.645 ; 6.591,-53.62 6.997,-53.62 ; 6.591,-53.594 6.997,-53.594 ; 6.591,-53.569 6.997,-53.569 ; 6.591,-53.543 6.997,-53.543 ; 6.604,-55.458 6.807,-55.458 ; 6.604,-55.205 6.807,-55.205 ; 6.616,-56.287 6.769,-56.287 ; 6.616,-56.033 6.896,-56.033 ; 6.629,-55.433 6.807,-55.433 ; 6.629,-55.407 6.807,-55.407 ; 6.629,-55.382 6.832,-55.382 ; 6.629,-55.357 6.832,-55.357 ; 6.629,-55.332 6.832,-55.332 ; 6.629,-55.306 6.832,-55.306 ; 6.629,-55.281 6.832,-55.281 ; 6.629,-55.255 6.807,-55.255 ; 6.629,-55.23 6.807,-55.23 ; 6.642,-56.312 6.82,-56.312 ; 6.667,-56.337 6.845,-56.337 ; 6.693,-56.363 6.87,-56.363 ; 6.693,-56.007 6.82,-56.007 ; 6.743,-56.388 6.896,-56.388 ; 6.769,-56.414 6.921,-56.414 ; 6.794,-56.109 6.947,-56.109 ; 6.82,-56.16 6.87,-56.16 ; 6.82,-56.134 6.972,-56.134 ; 6.883,-55.433 7.086,-55.433 ; 6.909,-55.484 7.137,-55.484 ; 6.909,-55.458 7.112,-55.458 ; 6.909,-55.23 7.086,-55.23 ; 6.909,-55.205 7.112,-55.205 ; 6.909,-55.179 7.137,-55.179 ; 6.934,-55.534 7.391,-55.534 ; 6.934,-55.509 7.417,-55.509 ; 6.934,-55.407 7.086,-55.407 ; 6.934,-55.154 7.417,-55.154 ; 6.934,-55.128 7.391,-55.128 ; 6.959,-55.56 7.366,-55.56 ; 6.959,-55.103 7.366,-55.103 ; 6.985,-55.585 7.34,-55.585 ; 6.985,-55.078 7.34,-55.078 ; 7.01,-55.382 7.086,-55.382 ; 7.01,-55.255 7.086,-55.255 ; 7.061,-55.611 7.29,-55.611 ; 7.061,-55.052 7.264,-55.052 ; 7.213,-55.484 7.417,-55.484 ; 7.213,-55.179 7.417,-55.179 ; 7.239,-55.458 7.442,-55.458 ; 7.239,-55.205 7.442,-55.205 ; 7.264,-55.433 7.442,-55.433 ; 7.264,-55.407 7.442,-55.407 ; 7.264,-55.382 7.467,-55.382 ; 7.264,-55.357 7.467,-55.357 ; 7.264,-55.332 7.467,-55.332 ; 7.264,-55.306 7.467,-55.306 ; 7.264,-55.281 7.467,-55.281 ; 7.264,-55.255 7.442,-55.255 ; 7.264,-55.23 7.442,-55.23 ; 7.759,-56.998 7.988,-56.998 ; 7.759,-56.972 7.988,-56.972 ; 7.759,-56.947 7.988,-56.947 ; 7.759,-56.922 7.988,-56.922 ; 7.759,-56.896 7.988,-56.896 ; 7.759,-56.871 7.988,-56.871 ; 7.759,-56.845 7.988,-56.845 ; 7.759,-56.82 7.988,-56.82 ; 7.759,-56.795 7.988,-56.795 ; 7.759,-56.769 7.988,-56.769 ; 7.759,-56.744 7.988,-56.744 ; 7.759,-56.718 7.988,-56.718 ; 7.759,-56.693 7.988,-56.693 ; 7.759,-56.668 7.988,-56.668 ; 7.759,-56.642 7.988,-56.642 ; 7.759,-56.617 7.988,-56.617 ; 7.759,-56.591 7.988,-56.591 ; 7.759,-56.566 7.988,-56.566 ; 7.759,-56.541 7.988,-56.541 ; 7.759,-56.515 7.988,-56.515 ; 7.759,-56.49 7.988,-56.49 ; 7.759,-56.464 7.988,-56.464 ; 7.759,-56.439 7.988,-56.439 ; 7.759,-56.414 7.988,-56.414 ; 7.759,-56.388 7.988,-56.388 ; 7.759,-56.363 7.988,-56.363 ; 7.759,-56.337 7.988,-56.337 ; 7.759,-56.312 7.988,-56.312 ; 7.759,-56.287 7.988,-56.287 ; 7.759,-56.261 7.988,-56.261 ; 7.759,-56.236 7.988,-56.236 ; 7.759,-56.21 7.988,-56.21 ; 7.759,-56.185 7.988,-56.185 ; 7.759,-56.16 7.988,-56.16 ; 7.759,-56.134 7.988,-56.134 ; 7.759,-56.109 7.988,-56.109 ; 7.759,-56.083 7.988,-56.083 ; 7.759,-56.058 7.988,-56.058 ; 7.759,-56.033 7.988,-56.033 ; 7.759,-56.007 7.988,-56.007 ; 7.759,-55.982 7.988,-55.982 ; 7.759,-55.956 7.988,-55.956 ; 7.759,-55.931 7.988,-55.931 ; 7.759,-55.906 7.988,-55.906 ; 7.759,-55.88 7.988,-55.88 ; 7.759,-55.855 7.988,-55.855 ; 7.759,-55.829 7.988,-55.829 ; 7.759,-55.804 7.988,-55.804 ; 7.759,-55.779 7.988,-55.779 ; 7.759,-55.753 7.988,-55.753 ; 7.759,-55.728 7.988,-55.728 ; 7.759,-55.702 7.988,-55.702 ; 7.759,-55.677 7.988,-55.677 ; 7.759,-55.652 7.988,-55.652 ; 7.759,-55.626 7.988,-55.626 ; 7.759,-55.601 7.988,-55.601 ; 7.759,-55.575 7.988,-55.575 ; 7.759,-55.55 7.988,-55.55 ; 7.759,-55.525 7.988,-55.525 ; 7.759,-55.499 7.988,-55.499 ; 7.759,-55.474 7.988,-55.474 ; 7.759,-55.448 7.988,-55.448 ; 7.759,-55.423 7.988,-55.423 ; 7.759,-55.398 7.988,-55.398 ; 7.759,-55.372 7.988,-55.372 ; 7.759,-55.347 7.988,-55.347 ; 7.759,-55.321 7.988,-55.321 ; 7.759,-55.296 7.988,-55.296 ; 7.759,-55.271 7.988,-55.271 ; 7.759,-55.245 7.988,-55.245 ; 7.759,-55.22 7.988,-55.22 ; 7.759,-55.194 7.988,-55.194 ; 7.759,-55.169 7.988,-55.169 ; 7.759,-55.144 7.988,-55.144 ; 7.759,-55.118 7.988,-55.118 ; 7.759,-55.093 7.988,-55.093 ; 7.759,-55.067 7.988,-55.067 ; 7.759,-55.042 7.988,-55.042 ; 7.759,-55.017 7.988,-55.017 ; 7.759,-54.991 7.988,-54.991 ; 7.759,-54.966 7.988,-54.966 ; 7.759,-54.94 7.988,-54.94 ; 7.759,-54.915 7.988,-54.915 ; 7.759,-54.89 7.988,-54.89 ; 7.759,-54.864 7.988,-54.864 ; 7.759,-54.839 7.988,-54.839 ; 7.759,-54.813 7.988,-54.813 ; 7.759,-54.788 7.988,-54.788 ; 7.759,-54.763 7.988,-54.763 ; 7.759,-54.737 7.988,-54.737 ; 7.759,-54.712 7.988,-54.712 ; 7.759,-54.686 7.988,-54.686 ; 7.759,-54.661 7.988,-54.661 ; 7.759,-54.636 7.988,-54.636 ; 7.759,-54.61 7.988,-54.61 ; 7.759,-54.585 7.988,-54.585 ; 7.759,-54.559 7.988,-54.559 ; 7.759,-54.534 7.988,-54.534 ; 7.759,-54.509 7.988,-54.509 ; 7.759,-54.483 7.988,-54.483 ; 7.759,-54.458 7.988,-54.458 ; 7.759,-54.432 7.988,-54.432 ; 7.759,-54.407 7.988,-54.407 ; 7.759,-54.382 7.988,-54.382 ; 7.759,-54.356 7.988,-54.356 ; 7.759,-54.331 7.988,-54.331 ; 7.759,-54.305 7.988,-54.305 ; 7.759,-54.28 7.988,-54.28 ; 7.759,-54.255 7.988,-54.255 ; 7.759,-54.229 7.988,-54.229 ; 7.759,-54.204 7.988,-54.204 ; 7.759,-54.178 7.988,-54.178 ; 7.759,-54.153 7.988,-54.153 ; 7.759,-54.128 7.988,-54.128 ; 7.759,-54.102 7.988,-54.102 ; 7.759,-54.077 7.988,-54.077 ; 7.759,-54.051 7.988,-54.051 ; 7.759,-54.026 7.988,-54.026 ; 7.759,-54.001 7.988,-54.001 ; 7.759,-53.975 7.988,-53.975 ; 7.759,-53.95 7.988,-53.95 ; 7.759,-53.924 7.988,-53.924 ; 7.759,-53.899 7.988,-53.899 ; 7.759,-53.874 7.988,-53.874 ; 7.759,-53.848 7.988,-53.848 ; 7.759,-53.823 7.988,-53.823 ; 7.759,-53.797 7.988,-53.797 ; 7.759,-53.772 7.988,-53.772 ; 7.759,-53.747 7.988,-53.747 ; 7.759,-53.721 7.988,-53.721 ; 7.759,-53.696 7.988,-53.696 ; 7.759,-53.67 7.988,-53.67 ; 7.759,-53.645 7.988,-53.645 ; 7.759,-53.62 7.988,-53.62 ; 7.759,-53.594 7.988,-53.594 ; 7.759,-53.569 7.988,-53.569 ; 7.759,-53.543 7.988,-53.543 ; 7.759,-53.518 7.988,-53.518 ; 7.759,-53.493 7.988,-53.493 ; 7.759,-53.467 7.988,-53.467 ; 7.759,-53.442 7.988,-53.442 ; 7.759,-53.416 7.988,-53.416 ; 7.759,-53.391 7.988,-53.391 ; 7.759,-53.366 7.988,-53.366 ; 7.759,-53.34 7.988,-53.34 ; 7.759,-53.315 7.988,-53.315 ; 7.759,-53.289 7.988,-53.289 ; 7.759,-53.264 7.988,-53.264 ; 7.759,-53.239 7.988,-53.239 ; 7.759,-53.213 7.988,-53.213 ; 7.759,-53.188 7.988,-53.188 ; 7.759,-53.162 7.988,-53.162 ; 7.759,-53.137 7.988,-53.137 ; 7.759,-53.112 7.988,-53.112 ; 7.759,-53.086 7.988,-53.086 ; 7.759,-53.061 7.988,-53.061 ; 7.759,-53.035 7.988,-53.035 ; 7.759,-53.01 7.988,-53.01 ; 7.759,-52.985 7.988,-52.985 ; 7.759,-52.959 7.988,-52.959 ; 7.759,-52.934 7.988,-52.934 ; 7.759,-52.908 7.988,-52.908 ; 7.759,-52.883 7.988,-52.883 ; 7.759,-52.858 7.988,-52.858 ; 7.759,-52.832 7.988,-52.832 ; 7.759,-52.807 7.988,-52.807 ; 7.759,-52.781 7.988,-52.781 ; 7.759,-52.756 7.988,-52.756 ; 7.759,-52.731 7.988,-52.731 ; 7.759,-52.705 7.988,-52.705 ; 7.759,-52.68 7.988,-52.68
Keep-Out Layer:
  lines w0.6: -16.285,-51.502 38.859,-51.502 ; 11.518,-80.475 11.518,-28.259

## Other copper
Top Layer:
  rectangle net Vin: -0.769,-45.572 5.6,-43.804
  rectangle net Vin: 24.702,-44.66 25.439,-43.843
  rectangle net Vin: 24.514,-44.186 25.131,-43.833
  rectangle net Vin: -1.003,-44.736 -0.266,-43.919
  rectangle net Vout: -2.76,-44.691 -1.882,-43.759
  rectangle net Vout: -8.413,-45.524 -2.219,-43.716
  rectangle net Vout: -5.971,-44.093 -1.889,-43.555
  rectangle net Vin: -0.965,-44.094 3.36,-43.565
  rectangle net Vout: 20.138,-64.301 24.919,-60.928
  rectangle net Vin: -0.572,-65.957 3.471,-65.381
  rectangle net Vin: 0.052,-65.485 3.121,-64.522
  rectangle net Vin: 2.005,-65.426 3.557,-63.996
  rectangle net Vout: -7.528,-66.202 -2.696,-64.407
  rectangle net Vout: -4.873,-66.018 -2.606,-61.841
  rectangle net Vout: -2.932,-65.95 -2.28,-64.834
  rectangle net Vout: -3.945,-65.624 -2.468,-64.456
  rectangle net Vout: -3.302,-66.079 -2.134,-65.546
  rectangle net Vin: 24.678,-43.873 29.078,-43.545
  rectangle net Vout: 19.73,-43.864 23.863,-43.542
  rectangle net Vout: 17.296,-45.507 23.49,-43.699
  rectangle net Vout: 22.949,-44.674 23.827,-43.742
  rectangle net Vout: 23.66,-44.176 24.051,-43.825
  rectangle net Vin: 24.94,-45.555 31.309,-43.787

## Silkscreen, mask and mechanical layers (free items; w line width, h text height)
Top Overlay:
  lines w0.005: 24.239,-43.426 24.295,-43.482 ; 24.242,-43.478 24.295,-43.427
  lines w0.02: -1.884,-43.919 -1.884,-43.827 ; -0.971,-43.919 -0.971,-43.832
  lines w0.15: -15.362,-49.956 -12.565,-49.956 ; -15.338,-49.944 -15.338,-30.417 ; -15.332,-30.405 -12.535,-30.405 ; -15.275,-73.162 -15.275,-58.112 -13.547,-58.112 -13.547,-73.183 -15.253,-73.183 ; -12.572,-49.9 -12.572,-30.373 ; -11.942,-49.966 -11.942,-48.165 ; -11.921,-49.923 -0.246,-49.923 ; -11.921,-48.143 -0.267,-48.143 ; -11.863,-54.657 -11.863,-52.856 ; -11.842,-54.614 -0.167,-54.614 ; -11.842,-52.834 -0.188,-52.834 ; -1.884,-43.922 -1.884,-43.026 -0.971,-43.026 -0.971,-43.917 ; -1.884,-43.92 -0.971,-43.92 ; -0.868,-67.209 -0.868,-65.646 ; -0.868,-67.206 -2.28,-67.206 -2.279,-65.645 -0.865,-65.645 ; -0.246,-49.944 -0.246,-48.186 ; -0.167,-54.635 -0.167,-52.877 ; 24.696,-63.969 24.696,-63.835 ; 24.696,-63.842 25.004,-63.842 ; 24.703,-65.919 24.703,-65.8 ; 24.707,-65.922 25.029,-65.922 ; 26.04,-48.155 26.04,-49.913 37.736,-49.913 ; 26.061,-48.133 37.715,-48.133 ; 26.072,-54.658 26.072,-52.857 ; 26.072,-52.852 37.699,-52.852 37.718,-52.871 37.718,-54.637 ; 26.102,-54.632 37.733,-54.632 ; 26.443,-65.922 26.768,-65.922 ; 26.455,-63.842 26.757,-63.842 ; 26.763,-63.975 26.763,-63.857 ; 26.769,-65.909 26.769,-65.793 ; 37.736,-49.934 37.736,-48.176 ; 23.857,-43.855 24.685,-43.855 24.685,-43.046 23.857,-43.046 23.857,-43.855
  lines w0.254: -14.829,-62.143 -14.035,-62.568 ; -14.829,-61.148 -14.041,-61.577
  text "1" at -100.425,26.874 h0.38
  text "Vout_s" at -11.747,-30.062 h0.7 r315
  text "Vout_s" at 13.729,-30.113 h0.7 r315
  text "Vout_f" at -9.264,-30.164 h0.7 r315
  text "Vout_f" at 16.38,-30.25 h0.7 r315
  text "Vin_s" at 6.226,-30.42 h0.7 r315
  text "Vin_s" at 32.123,-30.503 h0.7 r315
  text "Vin_f" at 3.717,-30.651 h0.7 r315
  text "Vin_f" at 29.499,-30.715 h0.7 r315
  text "GND" at -3.733,-31.291 h0.7 r315
  text "GND" at -1.173,-31.368 h0.7 r315
  text "GND" at 22.177,-31.456 h0.7 r315
  text "GND" at 24.717,-31.477 h0.7 r315
  text "EN" at 1.72,-31.726 h0.7 r315
  text "EN" at 27.448,-31.793 h0.7 r315
  text "NOT FCC" at -14.224,-35.602 h0.7 r90
  text "CN3" at 10.022,-36.466 h0.7 r90
  text "CN4" at 35.731,-36.548 h0.7 r90
  text "EN" at 28.06,-39.75 h0.7 r45
  text "EN" at 2.155,-39.919 h0.7 r45
  text "GND" at -0.226,-40.124 h0.7 r45
  text "GND" at -3.196,-40.175 h0.7 r45
  text "GND" at 22.474,-40.195 h0.7 r45
  text "GND" at 25.394,-40.237 h0.7 r45
  text "Vin_f" at 4.229,-40.969 h0.7 r45
  text "Vin_f" at 30.067,-40.979 h0.7 r45
  text "Vin_s" at 32.295,-41.057 h0.7 r45
  text "Vin_s" at 6.559,-41.148 h0.7 r45
  text "Vout_s" at -11.538,-41.393 h0.7 r45
  text "Vout_s" at 14.059,-41.468 h0.7 r45
  text "Vout_f" at -8.777,-41.507 h0.7 r45
  text "Vout_f" at 16.776,-41.507 h0.7 r45
  text "." at -0.743,-42.736 h0.9
  text "U4" at 25.202,-43.681 h0.7
  text "U3" at -0.442,-43.794 h0.7
  text "." at 24.975,-44.142 h0.9
  text "LDLN025J33R" at 26.532,-49.473 h1
  text "LDBL20D-25R" at -11.514,-49.551 h1
  text "FOR EVALUATION ONLY-" at -14.19,-49.649 h0.7 r90
  text "APPROVED FOR RESALE" at -13.062,-50.427 h0.7 r90
  text "STLQ020PUR" at 27.138,-54.256 h1
  text "LD39130SPUR" at -11.341,-54.275 h1
  text "." at 24.17,-63.736 h0.9
  text "U2" at 27.367,-65.198 h0.7
  text "U1" at -0.329,-66.799 h0.7
  text "." at -2.732,-67.015 h0.9
  text "Vout_f" at 15.585,-68.892 h0.7 r315
  text "Vout_s" at 13.443,-68.92 h0.7 r315
  text "Vout_f" at -8.474,-68.94 h0.7 r315
  text "Vout_s" at -10.358,-68.955 h0.7 r315
  text "Vin_s" at 31.146,-69.261 h0.7 r315
  text "Vin_f" at 28.465,-69.292 h0.7 r315
  text "Vin_s" at 7.087,-69.309 h0.7 r315
  text "Vin_f" at 4.406,-69.34 h0.7 r315
  text "GND" at 24.349,-70.468 h0.7 r315
  text "GM" at -4.931,-70.511 h0.7 r315
  text "GND" at 21.778,-70.499 h0.7 r315
  text "EN" at 26.924,-70.525 h0.7 r315
  text "EN" at 2.865,-70.573 h0.7 r315
  text "GND" at -2.681,-71.559 h0.7
  text "GND" at -0.001,-71.559 h0.7
  text "STEVAL-LDO001V1" at -13.935,-72.691 h1 r90
  text "CN1" at -11.092,-75.091 h0.7 r90
  text "CN2" at 35.522,-75.346 h0.7 r90
  text "EN" at 27.417,-78.721 h0.7 r45
  text "EN" at 3.358,-78.769 h0.7 r45
  text "GM" at -4.715,-78.893 h0.7 r45
  text "GND" at 21.56,-79.112 h0.7 r45
  text "GND" at -2.499,-79.16 h0.7 r45
  text "GND" at 24.287,-79.236 h0.7 r45
  text "GND" at 0.228,-79.284 h0.7 r45
  text "Vin_f" at 28.804,-79.954 h0.7 r45
  text "Vin_f" at 4.745,-80.002 h0.7 r45
  text "Vin_s" at 31.577,-80.016 h0.7 r45
  text "Vin_s" at 7.518,-80.064 h0.7 r45
  text "Vout_s" at 13.181,-80.262 h0.7 r45
  text "Vout_s" at -10.878,-80.31 h0.7 r45
  text "Vout_f" at -8.484,-80.303 h0.7 r45
  text "Vout_f" at 15.854,-80.325 h0.7 r45
Bottom Overlay:
  drawing of 4870 lines, arcs and shapes, not listed
Mechanical 1:
  lines w0.254: -16.216,-80.717 -16.216,-27.877 ; -16.17,-80.717 38.985,-80.717 ; -16.128,-27.909 38.957,-27.909 ; 38.957,-80.694 38.957,-27.93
